VERSION 5.8 ;
BUSBITCHARS "[]" ;
DIVIDERCHAR "/" ;

VIA PYL1_C_0
  VIARULE PYL1_C ;
  CUTSIZE 0.17 0.17 ;
  LAYERS poly licon1 li1 ;
  CUTSPACING 0.17 0.17 ;
  ENCLOSURE 0.08 0.08 0.08 0.08 ;
  ROWCOL 1 1 ;
END PYL1_C_0

VIA PYL1_C_1
  VIARULE PYL1_C ;
  CUTSIZE 0.17 0.17 ;
  LAYERS poly licon1 li1 ;
  CUTSPACING 0.17 0.17 ;
  ENCLOSURE 0.08 0.08 0.08 0.08 ;
  ROWCOL 1 2 ;
END PYL1_C_1

VIA PYL1_C_2
  VIARULE PYL1_C ;
  CUTSIZE 0.17 0.17 ;
  LAYERS poly licon1 li1 ;
  CUTSPACING 0.17 0.17 ;
  ENCLOSURE 0.08 0.08 0.08 0.08 ;
  ROWCOL 1 5 ;
END PYL1_C_2

VIA PYL1_C_3
  VIARULE PYL1_C ;
  CUTSIZE 0.17 0.17 ;
  LAYERS poly licon1 li1 ;
  CUTSPACING 0.17 0.17 ;
  ENCLOSURE 0.08 0.08 0.08 0.08 ;
  ROWCOL 1 24 ;
END PYL1_C_3

VIA PYL1_C_4
  VIARULE PYL1_C ;
  CUTSIZE 0.17 0.17 ;
  LAYERS poly licon1 li1 ;
  CUTSPACING 0.17 0.17 ;
  ENCLOSURE 0.08 0.08 0.08 0.08 ;
  ROWCOL 1 21 ;
END PYL1_C_4

VIA PYL1_C_5
  VIARULE PYL1_C ;
  CUTSIZE 0.17 0.17 ;
  LAYERS poly licon1 li1 ;
  CUTSPACING 0.17 0.17 ;
  ENCLOSURE 0.08 0.08 0.08 0.08 ;
  ROWCOL 1 8 ;
END PYL1_C_5

VIA L1M1_C_6
  VIARULE L1M1_C ;
  CUTSIZE 0.17 0.17 ;
  LAYERS li1 mcon met1 ;
  CUTSPACING 0.19 0.19 ;
  ENCLOSURE 0 0 0.06 0.06 ;
  ROWCOL 1 1 ;
END L1M1_C_6

VIA L1M1_C_7
  VIARULE L1M1_C ;
  CUTSIZE 0.17 0.17 ;
  LAYERS li1 mcon met1 ;
  CUTSPACING 0.19 0.19 ;
  ENCLOSURE 0 0 0.06 0.06 ;
  ROWCOL 1 2 ;
END L1M1_C_7

VIA L1M1_C_8
  VIARULE L1M1_C ;
  CUTSIZE 0.17 0.17 ;
  LAYERS li1 mcon met1 ;
  CUTSPACING 0.19 0.19 ;
  ENCLOSURE 0 0 0.06 0.06 ;
  ROWCOL 1 22 ;
END L1M1_C_8

VIA L1M1_C_9
  VIARULE L1M1_C ;
  CUTSIZE 0.17 0.17 ;
  LAYERS li1 mcon met1 ;
  CUTSPACING 0.19 0.19 ;
  ENCLOSURE 0 0 0.06 0.06 ;
  ROWCOL 1 20 ;
END L1M1_C_9

VIA M1M2_C_10
  VIARULE M1M2_C ;
  CUTSIZE 0.15 0.15 ;
  LAYERS met1 via met2 ;
  CUTSPACING 0.17 0.17 ;
  ENCLOSURE 0.085 0.085 0.085 0.085 ;
  ROWCOL 1 1 ;
END M1M2_C_10

VIA M1M2_C_11
  VIARULE M1M2_C ;
  CUTSIZE 0.15 0.15 ;
  LAYERS met1 via met2 ;
  CUTSPACING 0.17 0.17 ;
  ENCLOSURE 0.085 0.085 0.085 0.085 ;
  ROWCOL 2 2 ;
END M1M2_C_11

VIA M1M2_C_12
  VIARULE M1M2_C ;
  CUTSIZE 0.15 0.15 ;
  LAYERS met1 via met2 ;
  CUTSPACING 0.17 0.17 ;
  ENCLOSURE 0.085 0.085 0.085 0.085 ;
  ROWCOL 4 1 ;
END M1M2_C_12

VIA M1M2_C_13
  VIARULE M1M2_C ;
  CUTSIZE 0.15 0.15 ;
  LAYERS met1 via met2 ;
  CUTSPACING 0.17 0.17 ;
  ENCLOSURE 0.085 0.085 0.085 0.085 ;
  ROWCOL 2 1 ;
END M1M2_C_13

VIA M1M2_C_14
  VIARULE M1M2_C ;
  CUTSIZE 0.15 0.15 ;
  LAYERS met1 via met2 ;
  CUTSPACING 0.17 0.17 ;
  ENCLOSURE 0.085 0.085 0.085 0.085 ;
  ROWCOL 1 2 ;
END M1M2_C_14

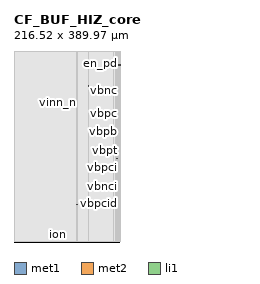
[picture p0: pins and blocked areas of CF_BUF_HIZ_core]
MACRO CF_BUF_HIZ_core
  ORIGIN 1.085 1.435 ;
  SIZE 216.52 BY 389.97 ;
  PIN tp
    DIRECTION INPUT ;
    USE SIGNAL ;
    PORT
      LAYER met1 ;
        RECT 91.255 286.72 91.37 286.995 ;
    END
  END tp
  PIN vpb_a
    DIRECTION INOUT ;
    USE SIGNAL ;
    PORT
      LAYER met1 ;
        RECT 215.725 361.455 216.015 361.985 ;
    END
  END vpb_a
  PIN vnb
    DIRECTION INOUT ;
    USE SIGNAL ;
    PORT
      LAYER met1 ;
        RECT 216.225 361.455 216.515 361.985 ;
    END
  END vnb
  PIN vgnd_a
    DIRECTION INOUT ;
    USE SIGNAL ;
    PORT
      LAYER met1 ;
        RECT 213.235 361.455 214.115 361.985 ;
    END
  END vgnd_a
  PIN clk2_boost
    DIRECTION INPUT ;
    USE SIGNAL ;
    PORT
      LAYER met1 ;
        RECT 89.555 286.72 89.67 286.995 ;
    END
  END clk2_boost
  PIN clk1_boostr
    DIRECTION INPUT ;
    USE SIGNAL ;
    PORT
      LAYER met1 ;
        RECT 90.02 286.72 90.135 286.995 ;
    END
  END clk1_boostr
  PIN vbpt
    DIRECTION INPUT ;
    USE SIGNAL ;
    PORT
      LAYER met2 ;
        RECT 208.495 169.63 208.98 169.745 ;
        RECT 214.03 133.345 214.42 133.465 ;
        RECT 210.08 169.61 210.55 169.75 ;
    END
  END vbpt
  PIN vbpcis
    DIRECTION INOUT ;
    USE SIGNAL ;
    PORT
      LAYER met2 ;
        RECT 209.955 168.95 210.625 169.09 ;
    END
  END vbpcis
  PIN vbncis
    DIRECTION INOUT ;
    USE SIGNAL ;
    PORT
      LAYER met2 ;
        RECT 207.635 145.29 208.105 145.43 ;
    END
  END vbncis
  PIN vpwr_a
    DIRECTION INOUT ;
    USE SIGNAL ;
    PORT
      LAYER met1 ;
        RECT 214.6 361.455 215.48 361.985 ;
    END
  END vpwr_a
  PIN vout
    DIRECTION OUTPUT ;
    USE SIGNAL ;
    PORT
      LAYER met2 ;
        RECT 127.875 75.545 128.605 75.98 ;
    END
  END vout
  PIN vbpci
    DIRECTION INPUT ;
    USE SIGNAL ;
    PORT
      LAYER met2 ;
        RECT 214.03 135.025 214.42 135.145 ;
    END
  END vbpci
  PIN vbnt
    DIRECTION INPUT ;
    USE SIGNAL ;
    PORT
      LAYER met2 ;
        RECT 211.235 114.58 211.425 114.685 ;
    END
  END vbnt
  PIN ibias
    DIRECTION INPUT ;
    USE SIGNAL ;
    PORT
      LAYER met2 ;
        RECT 152.59 318.695 152.725 318.795 ;
        RECT 152.59 298.55 152.725 298.65 ;
        RECT 151.925 318.645 152.43 318.875 ;
        RECT 151.79 298.515 152.295 298.745 ;
    END
  END ibias
  PIN ion
    DIRECTION INOUT ;
    USE SIGNAL ;
    PORT
      LAYER met1 ;
        RECT 89.89 0.07 90.06 0.235 ;
    END
  END ion
  PIN iop
    DIRECTION INOUT ;
    USE SIGNAL ;
    PORT
      LAYER met1 ;
        RECT 90.985 0.07 91.155 0.235 ;
    END
  END iop
  PIN e_pd
    DIRECTION INPUT ;
    USE SIGNAL ;
    PORT
      LAYER met1 ;
        RECT 211.17 364.6 211.32 364.875 ;
      LAYER li1 ;
        RECT 103.26 116.855 103.435 117.01 ;
    END
  END e_pd
  PIN vbnci
    DIRECTION INPUT ;
    USE SIGNAL ;
    PORT
      LAYER met2 ;
        RECT 211.235 112.905 211.425 113.01 ;
    END
  END vbnci
  PIN vbpcid
    DIRECTION INPUT ;
    USE SIGNAL ;
    PORT
      LAYER met2 ;
        RECT 215.66 77.52 216.095 77.645 ;
    END
  END vbpcid
  PIN vbptd
    DIRECTION INPUT ;
    USE SIGNAL ;
    PORT
      LAYER met2 ;
        RECT 215.66 78.37 216.095 78.495 ;
    END
  END vbptd
  PIN vbnc
    DIRECTION INOUT ;
    USE SIGNAL ;
    PORT
      LAYER met2 ;
        RECT 209.3 310.47 209.615 310.565 ;
    END
  END vbnc
  PIN vbpc
    DIRECTION INPUT ;
    USE SIGNAL ;
    PORT
      LAYER met2 ;
        RECT 210.725 263.105 210.935 263.21 ;
    END
  END vbpc
  PIN en_pd
    DIRECTION INPUT ;
    USE SIGNAL ;
    PORT
      LAYER met1 ;
        RECT 211.58 364.6 211.73 364.875 ;
    END
  END en_pd
  PIN vbpb
    DIRECTION INPUT ;
    USE SIGNAL ;
    PORT
      LAYER met2 ;
        RECT 202.16 209.6 202.565 209.795 ;
    END
  END vbpb
  PIN vinp_n
    DIRECTION INOUT ;
    USE SIGNAL ;
    PORT
      LAYER met1 ;
        RECT 87.775 285.555 87.92 285.71 ;
    END
  END vinp_n
  PIN vinn_n
    DIRECTION INOUT ;
    USE SIGNAL ;
    PORT
      LAYER met1 ;
        RECT 88.19 285.545 88.335 285.7 ;
    END
  END vinn_n
  PIN vinp_na
    DIRECTION INOUT ;
    USE SIGNAL ;
    PORT
      LAYER met1 ;
        RECT 87.415 285.555 87.56 285.71 ;
    END
  END vinp_na
  PIN vinn_na
    DIRECTION INOUT ;
    USE SIGNAL ;
    PORT
      LAYER met1 ;
        RECT 87.025 285.555 87.17 285.71 ;
    END
  END vinn_na
  PIN vinn_p
    DIRECTION INOUT ;
    USE SIGNAL ;
    PORT
      LAYER met1 ;
        RECT 86.285 284.845 86.43 285 ;
    END
  END vinn_p
  PIN vinp_p
    DIRECTION INOUT ;
    USE SIGNAL ;
    PORT
      LAYER met1 ;
        RECT 86.66 285.13 86.805 285.285 ;
    END
  END vinp_p
  PIN e_na_boost
    DIRECTION INPUT ;
    USE SIGNAL ;
    PORT
      LAYER met1 ;
        RECT 90.53 286.72 90.645 286.995 ;
    END
  END e_na_boost
  PIN e_n_boost
    DIRECTION INPUT ;
    USE SIGNAL ;
    PORT
      LAYER met1 ;
        RECT 90.885 286.72 91 286.995 ;
    END
  END e_n_boost
  OBS
    LAYER li1 ;
      RECT 0 0 103.26 389.97 ;
      RECT 103.26 0 103.435 116.855 ;
      RECT 103.26 117.01 103.435 389.97 ;
      RECT 103.435 0 216.52 389.97 ;
    LAYER met1 ;
      RECT 0 0 86.285 389.97 ;
      RECT 86.285 0 86.43 284.845 ;
      RECT 86.285 285 86.43 389.97 ;
      RECT 86.43 0 86.66 389.97 ;
      RECT 86.66 0 86.805 285.13 ;
      RECT 86.66 285.285 86.805 389.97 ;
      RECT 86.805 0 87.025 389.97 ;
      RECT 87.025 0 87.17 285.555 ;
      RECT 87.025 285.71 87.17 389.97 ;
      RECT 87.17 0 87.415 389.97 ;
      RECT 87.415 0 87.56 285.555 ;
      RECT 87.415 285.71 87.56 389.97 ;
      RECT 87.56 0 87.775 389.97 ;
      RECT 87.775 0 87.92 285.555 ;
      RECT 87.775 285.71 87.92 389.97 ;
      RECT 87.92 0 88.19 389.97 ;
      RECT 88.19 0 88.335 285.545 ;
      RECT 88.19 285.7 88.335 389.97 ;
      RECT 88.335 0 89.555 389.97 ;
      RECT 89.555 0 89.67 286.72 ;
      RECT 89.555 286.995 89.67 389.97 ;
      RECT 89.67 0 89.89 389.97 ;
      RECT 89.89 0 90.02 0.07 ;
      RECT 89.89 0.235 90.02 389.97 ;
      RECT 90.02 0 90.06 0.07 ;
      RECT 90.02 0.235 90.06 286.72 ;
      RECT 90.02 286.995 90.06 389.97 ;
      RECT 90.06 0 90.135 286.72 ;
      RECT 90.06 286.995 90.135 389.97 ;
      RECT 90.135 0 90.53 389.97 ;
      RECT 90.53 0 90.645 286.72 ;
      RECT 90.53 286.995 90.645 389.97 ;
      RECT 90.645 0 90.885 389.97 ;
      RECT 90.885 0 90.985 286.72 ;
      RECT 90.885 286.995 90.985 389.97 ;
      RECT 90.985 0 91 0.07 ;
      RECT 90.985 0.235 91 286.72 ;
      RECT 90.985 286.995 91 389.97 ;
      RECT 91 0 91.155 0.07 ;
      RECT 91 0.235 91.155 389.97 ;
      RECT 91.155 0 91.255 389.97 ;
      RECT 91.255 0 91.37 286.72 ;
      RECT 91.255 286.995 91.37 389.97 ;
      RECT 91.37 0 211.17 389.97 ;
      RECT 211.17 0 211.32 364.6 ;
      RECT 211.17 364.875 211.32 389.97 ;
      RECT 211.32 0 211.58 389.97 ;
      RECT 211.58 0 211.73 364.6 ;
      RECT 211.58 364.875 211.73 389.97 ;
      RECT 211.73 0 213.235 389.97 ;
      RECT 213.235 0 214.115 361.455 ;
      RECT 213.235 361.985 214.115 389.97 ;
      RECT 214.115 0 214.6 389.97 ;
      RECT 214.6 0 215.48 361.455 ;
      RECT 214.6 361.985 215.48 389.97 ;
      RECT 215.48 0 215.725 389.97 ;
      RECT 215.725 0 216.015 361.455 ;
      RECT 215.725 361.985 216.015 389.97 ;
      RECT 216.015 0 216.225 389.97 ;
      RECT 216.225 0 216.515 361.455 ;
      RECT 216.225 361.985 216.515 389.97 ;
      RECT 216.515 0 216.52 389.97 ;
    LAYER met2 ;
      RECT 0 0 127.875 389.97 ;
      RECT 127.875 0 128.605 75.545 ;
      RECT 127.875 75.98 128.605 389.97 ;
      RECT 128.605 0 151.79 389.97 ;
      RECT 151.79 0 151.925 298.515 ;
      RECT 151.79 298.745 151.925 389.97 ;
      RECT 151.925 0 152.295 298.515 ;
      RECT 151.925 298.745 152.295 318.645 ;
      RECT 151.925 318.875 152.295 389.97 ;
      RECT 152.295 0 152.43 318.645 ;
      RECT 152.295 318.875 152.43 389.97 ;
      RECT 152.43 0 152.59 389.97 ;
      RECT 152.59 0 152.725 298.55 ;
      RECT 152.59 298.65 152.725 318.695 ;
      RECT 152.59 318.795 152.725 389.97 ;
      RECT 152.725 0 202.16 389.97 ;
      RECT 202.16 0 202.565 209.6 ;
      RECT 202.16 209.795 202.565 389.97 ;
      RECT 202.565 0 207.635 389.97 ;
      RECT 207.635 0 208.105 145.29 ;
      RECT 207.635 145.43 208.105 389.97 ;
      RECT 208.105 0 208.495 389.97 ;
      RECT 208.495 0 208.98 169.63 ;
      RECT 208.495 169.745 208.98 389.97 ;
      RECT 208.98 0 209.3 389.97 ;
      RECT 209.3 0 209.615 310.47 ;
      RECT 209.3 310.565 209.615 389.97 ;
      RECT 209.615 0 209.955 389.97 ;
      RECT 209.955 0 210.08 168.95 ;
      RECT 209.955 169.09 210.08 389.97 ;
      RECT 210.08 0 210.55 168.95 ;
      RECT 210.08 169.09 210.55 169.61 ;
      RECT 210.08 169.75 210.55 389.97 ;
      RECT 210.55 0 210.625 168.95 ;
      RECT 210.55 169.09 210.625 389.97 ;
      RECT 210.625 0 210.725 389.97 ;
      RECT 210.725 0 210.935 263.105 ;
      RECT 210.725 263.21 210.935 389.97 ;
      RECT 210.935 0 211.235 389.97 ;
      RECT 211.235 0 211.425 112.905 ;
      RECT 211.235 113.01 211.425 114.58 ;
      RECT 211.235 114.685 211.425 389.97 ;
      RECT 211.425 0 214.03 389.97 ;
      RECT 214.03 0 214.42 133.345 ;
      RECT 214.03 133.465 214.42 135.025 ;
      RECT 214.03 135.145 214.42 389.97 ;
      RECT 214.42 0 215.66 389.97 ;
      RECT 215.66 0 216.095 77.52 ;
      RECT 215.66 77.645 216.095 78.37 ;
      RECT 215.66 78.495 216.095 389.97 ;
      RECT 216.095 0 216.52 389.97 ;
  END
END CF_BUF_HIZ_core

END LIBRARY
